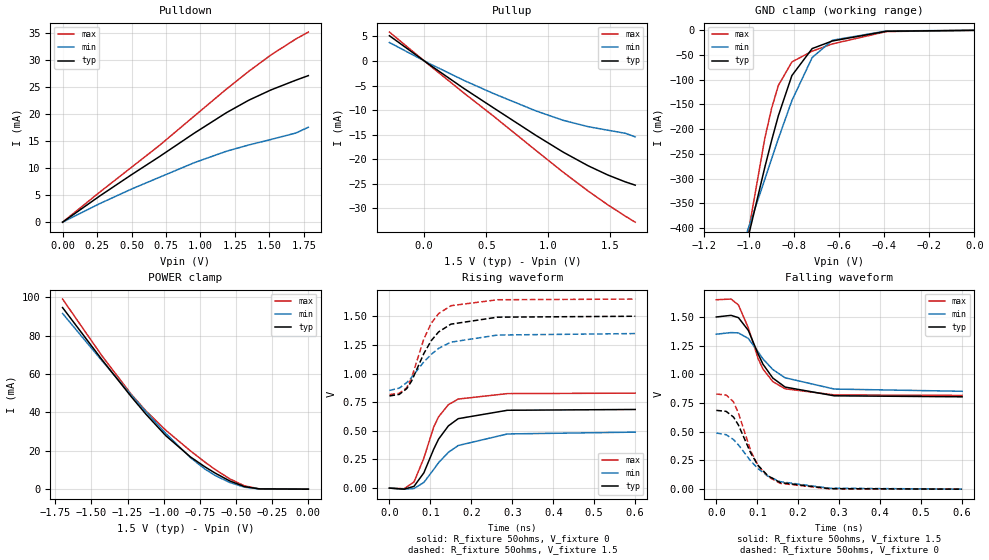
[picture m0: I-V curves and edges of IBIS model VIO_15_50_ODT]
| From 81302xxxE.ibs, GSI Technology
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[Model]   VIO_15_50_ODT
Model_type   I/O
Polarity   Non-Inverting
Vinl  =   0.5500V
Vinh  =   0.9500V
Vmeas =   0.75v
Rref  =   50
|  variable   typ   min   max
C_comp   3.0pF   2.5pF   3.5pF
[Receiver Thresholds]
Vth = 0.75V
Vth_min = 0.68V
Vth_max = 0.825V
Threshold_sensitivity = 1.0
Reference_supply Ext_ref
Vinh_ac = +200mv
Vinh_dc = +100mv
Vinl_ac = -200mv
Vinl_dc = -100mv
Tslew_ac = 550ps
|  variable   typ   min   max
[External Reference]   0.75   0.68   0.825
|  variable   typ   min   max
[Temperature Range]   50   100   0
|  variable   typ   min   max
[Voltage Range]   1.5   1.35   1.65
[Add Submodel]
| Submodel Name   Mode
Weak_ODT_18V   Non-Driving
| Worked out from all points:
|   slope of the pulldown table from 0 to 0.225 V, typ, clamps not added: 55.3 ohm
|   slope of the pullup table from 0 to 0.225 V, typ, clamps not added: 56.6 ohm
|   GND clamp passes 1 mA (typ) near -0.36 V on its own axis
|   POWER clamp passes 1 mA (typ) near -0.42 V on its own axis
|   rising waveform, R_fixture 50ohms, V_fixture 0: 20-80 % time 61.2ps typ, 83ps min, 52.4ps max; typ from 0 V to 0.686 V
|   rising waveform, R_fixture 50ohms, V_fixture 1.5: 20-80 % time 64.2ps typ, 84.3ps min, 54.3ps max; typ from 0.805 V to 1.5 V
|   falling waveform, R_fixture 50ohms, V_fixture 1.5: 20-80 % time 64ps typ, 86.7ps min, 55.1ps max; typ from 1.5 V to 0.805 V
|   falling waveform, R_fixture 50ohms, V_fixture 0: 20-80 % time 63.8ps typ, 81.5ps min, 56ps max; typ from 0.686 V to 0 V
[Pullup]
| V(VDDQ-Vout)   typ   min   max
-280mV    5.117mA    3.738mA    5.862mA
40mV      -717.8uA   -514.8uA   -829.9uA
320mV     -5.603mA   -3.96mA    -6.529mA
560mV     -9.572mA   -6.647mA   -11.26mA
900mV     -15.14mA   -10.16mA   -18.2mA
1.12V     -18.55mA   -12.08mA   -22.63mA
1.32V     -21.31mA   -13.36mA   -26.44mA
1.48V     -23.2mA    -14.09mA   -29.27mA
1.62V     -24.59mA   -14.71mA   -31.56mA
1.7V      -25.26mA   -15.44mA   -32.79mA
[PullDown]
| voltage   typ   min   max
0V        -5.688nA   -12.79nA   -2.55nA
270mV     4.867mA    3.451mA    5.58mA
504mV     8.871mA    6.187mA    10.26mA
702mV     12.15mA    8.318mA    14.22mA
954mV     16.49mA    11.02mA    19.65mA
1.188V    20.3mA     13.15mA    24.67mA
1.35V     22.61mA    14.31mA    27.97mA
1.512V    24.53mA    15.34mA    31.02mA
1.692V    26.33mA    16.53mA    33.97mA
1.782V    27.17mA    17.6mA     35.24mA
[POWER Clamp]
|V(VDDQ-Vout)   typ   min   max
-1.7V     94.64mA    91.58mA    99.09mA
-1.428V   67.54mA    66.99mA    69.55mA
-1.224V   48.12mA    49.01mA    49.38mA
-1.122V   38.97mA    40.27mA    40.69mA
-986mV    27.88mA    29.06mA    30.72mA
-816mV    16.83mA    16.48mA    19.99mA
-714mV    11.58mA    10.4mA     14.03mA
-646mV    8.438mA    7.201mA    10.33mA
-544mV    4.31mA     3.482mA    5.399mA
-442mV    1.34mA     1.042mA    1.733mA
-340mV    155.8uA    132.4uA    187.3uA
0V        29.97nA    53.04nA    12.57nA
[GND Clamp]
|(Vout)   typ   min   max
-1.5V     -1.259A    -998.1mA   -1.702A
-1.11V    -621.1mA   -540.5mA   -701.3mA
-1.08V    -564.5mA   -502.7mA   -615.1mA
-1.05V    -506.9mA   -463.9mA   -529.8mA
-930mV    -276.8mA   -301.4mA   -218mA
-900mV    -223mA     -260.1mA   -157.9mA
-870mV    -172.8mA   -219.3mA   -111.5mA
-810mV    -91.52mA   -142.2mA   -63.98mA
-720mV    -36.91mA   -55.08mA   -42.14mA
-630mV    -21.51mA   -20.02mA   -27.42mA
-390mV    -1.861mA   -1.298mA   -2.48mA
0V        -7.463nA   -15.47nA   -3.343nA
[Ramp]
| voltage   typ   min   max
dV/dt_r   0.54/186p   0.48/213p   0.60/209p
dV/dt_f   0.86/129p   0.66/166p   1.07/101p
R_load  =   50ohms
[Rising Waveform]
R_fixture =   50ohms
V_fixture =   0
| Time   V(typ)   V(min)   V(max)
0s        148nV      384.4nV    62.25nV
36ps      -9.245mV   -9.202mV   -5.346mV
60ps      15.38mV    -3.41mV    53.82mV
84ps      133.1mV    49.26mV    261.4mV
108ps     339.4mV    162.8mV    532.2mV
120ps     427.8mV    222.2mV    622.9mV
144ps     543.5mV    312.6mV    728.5mV
168ps     606.2mV    372mV      777.3mV
288ps     679.4mV    472.6mV    824.8mV
600ps     686.3mV    488.6mV    828.8mV
[Rising Waveform]
R_fixture =   50ohms
V_fixture =   1.5
V_fixture_min =  1.35
V_fixture_max =  1.65
| Time   V(typ)   V(min)   V(max)
0s        804.6mV    852.4mV    816.7mV
24ps      817.8mV    872.6mV    827mV
42ps      867.5mV    920.1mV    876.3mV
54ps      933.8mV    966.1mV    961.9mV
84ps      1.175V     1.102V     1.302V
102ps     1.287V     1.167V     1.439V
120ps     1.363V     1.219V     1.523V
150ps     1.431V     1.274V     1.592V
264ps     1.492V     1.336V     1.644V
600ps     1.5V       1.349V     1.65V
[Falling Waveform]
R_fixture =   50ohms
V_fixture =   1.5
V_fixture_min = 1.35
V_fixture_max = 1.65
| Time   V(typ)   V(min)   V(max)
0s        1.5V       1.35V      1.65V
36ps      1.514V     1.364V     1.656V
54ps      1.494V     1.361V     1.605V
78ps      1.384V     1.313V     1.406V
102ps     1.179V     1.197V     1.138V
114ps     1.088V     1.134V     1.046V
138ps     967.6mV    1.042V     936.8mV
168ps     889.3mV    970.2mV    874.3mV
288ps     813.2mV    872mV      821mV
600ps     804.6mV    852.7mV    816.7mV
[Falling Waveform]
R_fixture =   50ohms
V_fixture =   0
| Time   V(typ)   V(min)   V(max)
0s        686.5mV    488.9mV    828.8mV
24ps      677.6mV    474.5mV    820.2mV
42ps      628mV      431.4mV    760.4mV
54ps      558.5mV    385.5mV    663.1mV
84ps      314.7mV    245.4mV    333.6mV
102ps     206.5mV    178.3mV    204.8mV
126ps     116.4mV    113.8mV    108.9mV
156ps     57.7mV     65.47mV    50.68mV
276ps     4.891mV    8.677mV    3.283mV
600ps     22.39uV    89.08uV    5.871uV
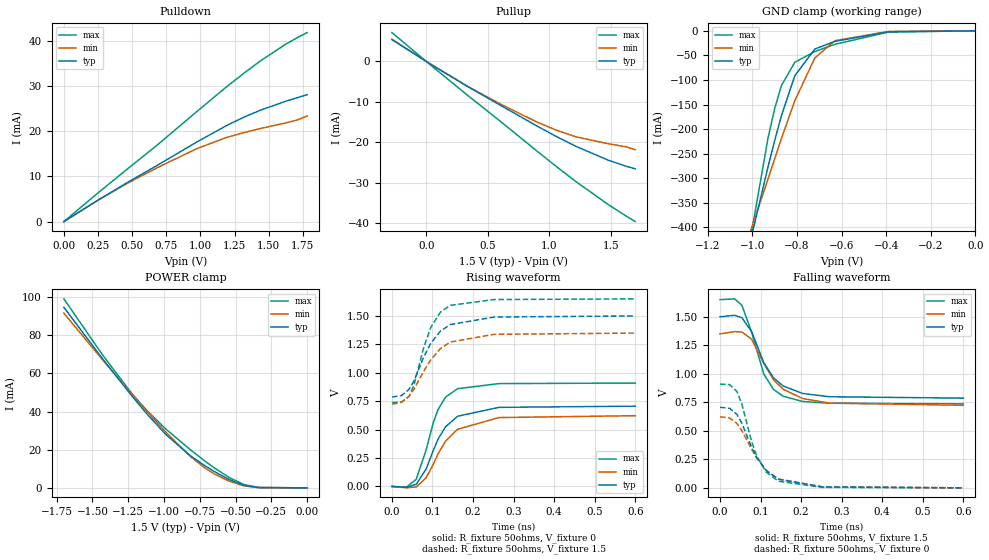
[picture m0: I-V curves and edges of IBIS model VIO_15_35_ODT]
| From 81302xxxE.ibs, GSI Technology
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[Model]   VIO_15_35_ODT
Model_type   I/O
Polarity   Non-Inverting
Vinl  =   0.5500V
Vinh  =   0.9500V
Vmeas =   0.75v
Rref  =   50
|  variable   typ   min   max
C_comp   3.0pF   2.5pF   3.5pF
[Receiver Thresholds]
Vth = 0.75V
Vth_min = 0.68V
Vth_max = 0.825V
Threshold_sensitivity = 1.0
Reference_supply Ext_ref
Vinh_ac = +200mv
Vinh_dc = +100mv
Vinl_ac = -200mv
Vinl_dc = -100mv
Tslew_ac = 550ps
|  variable   typ   min   max
[External Reference]   0.75   0.68   0.825
|  variable   typ   min   max
[Temperature Range]   50   100   0
|  variable   typ   min   max
[Voltage Range]   1.5   1.35   1.65
[Add Submodel]
| Submodel Name   Mode
Weak_ODT_15V   Non-Driving
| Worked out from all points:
|   slope of the pulldown table from 0 to 0.225 V, typ, clamps not added: 52.5 ohm
|   slope of the pullup table from 0 to 0.225 V, typ, clamps not added: 53.7 ohm
|   GND clamp passes 1 mA (typ) near -0.36 V on its own axis
|   POWER clamp passes 1 mA (typ) near -0.42 V on its own axis
|   rising waveform, R_fixture 50ohms, V_fixture 0: 20-80 % time 59.8ps typ, 67.7ps min, 47.5ps max; typ from 0 V to 0.706 V
|   rising waveform, R_fixture 50ohms, V_fixture 1.5: 20-80 % time 62.6ps typ, 70.5ps min, 48.9ps max; typ from 0.786 V to 1.5 V
|   falling waveform, R_fixture 50ohms, V_fixture 1.5: 20-80 % time 62.8ps typ, 71.4ps min, 49.9ps max; typ from 1.5 V to 0.786 V
|   falling waveform, R_fixture 50ohms, V_fixture 0: 20-80 % time 62.8ps typ, 68.3ps min, 50.3ps max; typ from 0.706 V to 0 V
[Pullup]
| V(VDDQ-Vout)   typ   min   max
-280mV    5.393mA    5.499mA    7.154mA
40mV      -756.8uA   -760.1uA   -1.014mA
340mV     -6.266mA   -6.207mA   -8.469mA
620mV     -11.13mA   -10.8mA    -15.22mA
900mV     -15.95mA   -14.97mA   -22.14mA
1.06V     -18.59mA   -17.01mA   -26.03mA
1.22V     -21.03mA   -18.66mA   -29.77mA
1.48V     -24.41mA   -20.34mA   -35.39mA
1.62V     -25.86mA   -21.07mA   -38.13mA
1.7V      -26.56mA   -21.82mA   -39.6mA
[PullDown]
| voltage   typ   min   max
0V        -5.746nA   -11.99nA   -2.475nA
252mV     4.789mA    4.764mA    6.393mA
468mV     8.7mA      8.52mA     11.71mA
684mV     12.45mA    11.93mA    16.95mA
972mV     17.59mA    16.13mA    24.32mA
1.188V    21.2mA     18.59mA    29.75mA
1.314V    23.06mA    19.67mA    32.75mA
1.44V     24.67mA    20.6mA     35.59mA
1.62V     26.59mA    21.82mA    39.19mA
1.71V     27.44mA    22.51mA    40.74mA
1.782V    28.11mA    23.38mA    41.86mA
[POWER Clamp]
|V(VDDQ-Vout)   typ   min   max
-1.7V     94.64mA    91.58mA    99.09mA
-1.428V   67.54mA    66.99mA    69.55mA
-1.224V   48.12mA    49.01mA    49.38mA
-1.122V   38.97mA    40.27mA    40.69mA
-986mV    27.88mA    29.06mA    30.72mA
-816mV    16.83mA    16.48mA    19.99mA
-714mV    11.58mA    10.4mA     14.03mA
-646mV    8.438mA    7.201mA    10.33mA
-544mV    4.31mA     3.482mA    5.399mA
-442mV    1.34mA     1.042mA    1.733mA
-340mV    155.8uA    132.4uA    187.3uA
0V        29.97nA    53.04nA    12.57nA
[GND Clamp]
|(Vout)   typ   min   max
-1.5V     -1.259A    -998.1mA   -1.702A
-1.11V    -621.1mA   -540.5mA   -701.3mA
-1.08V    -564.5mA   -502.7mA   -615.1mA
-1.05V    -506.9mA   -463.9mA   -529.8mA
-930mV    -276.8mA   -301.4mA   -218mA
-900mV    -223mA     -260.1mA   -157.9mA
-870mV    -172.8mA   -219.3mA   -111.5mA
-810mV    -91.52mA   -142.2mA   -63.98mA
-720mV    -36.91mA   -55.08mA   -42.14mA
-630mV    -21.51mA   -20.02mA   -27.42mA
-390mV    -1.861mA   -1.298mA   -2.48mA
0V        -7.463nA   -15.47nA   -3.343nA
[Ramp]
| voltage   typ   min   max
dV/dt_r   0.54/186p   0.48/213p   0.60/209p
dV/dt_f   0.86/129p   0.66/166p   1.07/101p
R_load  =   50ohms
[Rising Waveform]
R_fixture =   50ohms
V_fixture =   0
| Time   V(typ)   V(min)   V(max)
0s        145.8nV    302.9nV    54.13nV
36ps      -8.8mV     -12.42mV   -6.019mV
60ps      19.12mV    -4.075mV   63mV
84ps      151.2mV    74.4mV     316.8mV
102ps     315.4mV    194.9mV    561.2mV
114ps     418.1mV    288.1mV    677.9mV
132ps     524.1mV    397.1mV    784.7mV
162ps     617.5mV    503.3mV    859.9mV
264ps     695.6mV    605.8mV    904.7mV
600ps     706.2mV    622.4mV    909.4mV
[Rising Waveform]
R_fixture =   50ohms
V_fixture =   1.5
V_fixture_min =  1.35
V_fixture_max =  1.65
| Time   V(typ)   V(min)   V(max)
0s        786.4mV    723.5mV    736.6mV
24ps      800.2mV    740.2mV    742.9mV
42ps      853.6mV    793.7mV    790.9mV
54ps      925.8mV    852.8mV    886.8mV
78ps      1.135V     1.011V     1.217V
96ps      1.26V      1.115V     1.401V
120ps     1.368V     1.214V     1.535V
144ps     1.424V     1.27V      1.593V
252ps     1.49V      1.338V     1.644V
600ps     1.5V       1.349V     1.65V
[Falling Waveform]
R_fixture =   50ohms
V_fixture =   1.5
V_fixture_min = 1.35
V_fixture_max = 1.65
| Time   V(typ)   V(min)   V(max)
0s        1.5V       1.35V      1.65V
36ps      1.513V     1.37V      1.657V
54ps      1.492V     1.366V     1.601V
78ps      1.369V     1.304V     1.366V
108ps     1.098V     1.09V      997.7mV
132ps     964.2mV    947.9mV    862.7mV
156ps     892.7mV    864.3mV    802.8mV
204ps     827.6mV    783.1mV    757.5mV
270ps     798.8mV    743.4mV    741.5mV
600ps     786.5mV    723.7mV    736.6mV
[Falling Waveform]
R_fixture =   50ohms
V_fixture =   0
| Time   V(typ)   V(min)   V(max)
0s        706.4mV    622.7mV    909.5mV
24ps      697mV      612.4mV    905.1mV
42ps      643mV      562.9mV    843.6mV
54ps      566.9mV    503.1mV    732.2mV
78ps      355.2mV    339.4mV    406.6mV
90ps      268.5mV    263.7mV    283mV
114ps     151.7mV    153.1mV    137.8mV
144ps     75.73mV    77.58mV    58.34mV
252ps     8.293mV    9.236mV    4.113mV
600ps     23.78uV    56.63uV    4.292uV
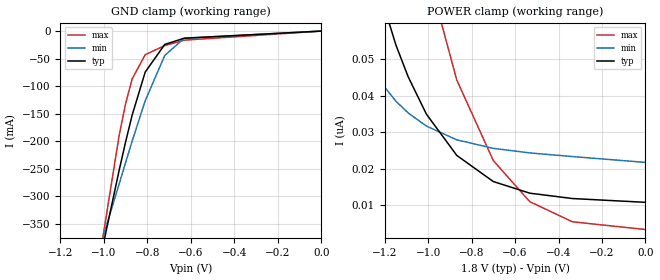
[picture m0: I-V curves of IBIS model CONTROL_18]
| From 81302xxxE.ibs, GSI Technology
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[Model]   CONTROL_18
Model_type   Input
Vinl  =   0.70v
Vinh  =   1.10v
|  variable   typ   min   max
C_comp   3.0pF   2.5pF   3.5pF
[Receiver Thresholds]
Vth = 0.90V
Vth_min = 0.80V
Vth_max = 0.95V
Threshold_sensitivity = 1.0
Reference_supply Ext_ref
Vinh_ac = +200mv
Vinh_dc = +100mv
Vinl_ac = -200mv
Vinl_dc = -100mv
Tslew_ac = 550ps
|  variable   typ   min   max
[External Reference]   0.90   0.80   0.95
|  variable   typ   min   max
[Temperature Range]   50   100   0
|  variable   typ   min   max
[Voltage Range]   1.8   1.6   2.0
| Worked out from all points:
|   GND clamp passes 1 mA (typ) near -0.40 V on its own axis
[POWER Clamp]
| voltage (VDDQ-Vout)   typ   min   max
-1.4V     117.3nA    64.47nA    259.5nA
-1.344V   99.16nA    56.66nA    221.8nA
-1.288V   83.53nA    50.16nA    188.4nA
-1.232V   70.19nA    44.79nA    159nA
-1.148V   53.93nA    38.53nA    121.7nA
-1.092V   45.27nA    35.34nA    101nA
-1.008V   35.01nA    31.73nA    75.22nA
-868mV    23.67nA    27.95nA    44.34nA
-700mV    16.51nA    25.61nA    22.26nA
-532mV    13.32nA    24.36nA    10.98nA
-336mV    11.85nA    23.36nA    5.479nA
0V        10.81nA    21.76nA    3.356nA
[Gnd Clamp]
| voltage (Vout)   typ   min   max
-1.5V     -1.188A    -928.4mA   -1.627A
-1.11V    -584.1mA   -502.9mA   -660.6mA
-1.08V    -529.8mA   -467.4mA   -576.7mA
-1.05V    -474.5mA   -431mA     -493.4mA
-1.02V    -418.6mA   -393.7mA   -411.7mA
-930mV    -252.7mA   -277.5mA   -189.5mA
-900mV    -200.7mA   -238.2mA   -131.2mA
-870mV    -152.3mA   -199.5mA   -86.68mA
-810mV    -74.31mA   -126.3mA   -42.82mA
-720mV    -24.21mA   -44.15mA   -26.24mA
-630mV    -12.89mA   -13.05mA   -16.43mA
0V        0A         0A         0A
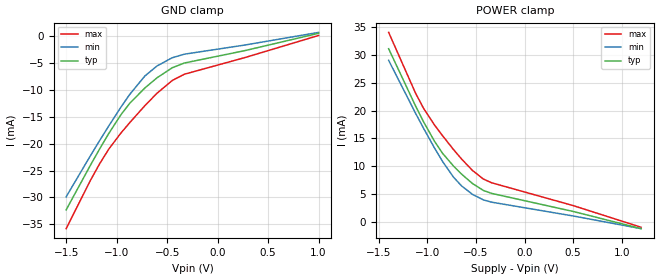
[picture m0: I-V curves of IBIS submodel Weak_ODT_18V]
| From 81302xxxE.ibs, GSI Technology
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[Submodel]   Weak_ODT_18V
Submodel_type   Dynamic_clamp
[Power Clamp]
-1.4V     31.12mA    29.03mA    34.06mA
-1.124V   20.86mA    19.56mA    23.17mA
-1.04V    17.97mA    16.8mA     20.39mA
-928mV    14.48mA    13.28mA    17.41mA
-844mV    12.3mA     10.83mA    15.46mA
-732mV    10.02mA    8.022mA    12.99mA
-648mV    8.559mA    6.44mA     11.27mA
-536mV    6.871mA    4.928mA    9.224mA
-424mV    5.636mA    3.938mA    7.685mA
-340mV    5.112mA    3.533mA    7.022mA
500mV     1.863mA    1.051mA    2.918mA
1.2V      -1.23mA    -1.231mA   -982.8uA
[GND Clamp]
-1.5V     -32.31mA   -29.88mA   -35.81mA
-1.26V    -24.01mA   -22.24mA   -26.84mA
-1.17V    -21.02mA   -19.46mA   -23.78mA
-1.08V    -18.15mA   -16.74mA   -21.05mA
-960mV    -14.66mA   -13.25mA   -18.06mA
-870mV    -12.46mA   -10.8mA    -16.06mA
-720mV    -9.606mA   -7.377mA   -12.9mA
-600mV    -7.718mA   -5.515mA   -10.59mA
-450mV    -5.855mA   -3.99mA    -8.226mA
-330mV    -4.968mA   -3.324mA   -7.058mA
270mV     -2.658mA   -1.618mA   -3.956mA
1V        566.9uA    733.7uA    162.3uA
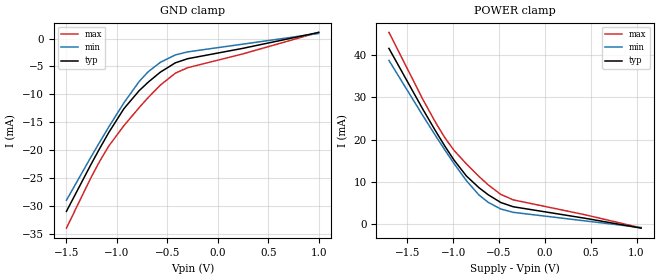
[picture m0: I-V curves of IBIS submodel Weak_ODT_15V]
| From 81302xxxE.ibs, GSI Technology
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[Submodel]  Weak_ODT_15V
Submodel_type Dynamic_clamp
[Power Clamp]
-1.7V     41.65mA    38.8mA     45.46mA
-1.33V    27.2mA     25.69mA    29.54mA
-1.194V   22.14mA    21.01mA    24.16mA
-1.092V   18.51mA    17.6mA     20.5mA
-990mV    15.12mA    14.3mA     17.43mA
-854mV    11.33mA    10.22mA    14.2mA
-718mV    8.578mA    6.846mA    11.24mA
-616mV    6.882mA    5.084mA    9.223mA
-480mV    5.059mA    3.519mA    6.981mA
-344mV    4.055mA    2.731mA    5.692mA
438mV     1.326mA    700.9uA    2.158mA
1.05V     -1.02mA    -880.1uA   -964.3uA
[GND Clamp]
-1.5V     -31mA      -29mA      -34.01mA
-1.26V    -22.69mA   -21.35mA   -25.05mA
-1.17V    -19.71mA   -18.57mA   -22mA
-1.08V    -16.84mA   -15.84mA   -19.27mA
-930mV    -12.57mA   -11.52mA   -15.62mA
-780mV    -9.364mA   -7.723mA   -12.4mA
-690mV    -7.827mA   -5.952mA   -10.58mA
-570mV    -6.032mA   -4.276mA   -8.367mA
-420mV    -4.345mA   -2.928mA   -6.201mA
-300mV    -3.617mA   -2.388mA   -5.237mA
240mV     -1.783mA   -1.019mA   -2.79mA
1V        1.101mA    920uA      1.115mA
